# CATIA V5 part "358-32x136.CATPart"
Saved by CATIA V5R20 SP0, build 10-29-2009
Part number: 358-32X136
Definition: NONE
Nomenclature: 358-32X136
Source: Unknown
Description: 358-32X136
Bounding box of the stored display mesh (mm): x -17 to 119, y -22.5 to 22.5, z -22.5 to 22.5
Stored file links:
  C:\Users\Utente\Desktop\IO LAVORO\3D X SITO CF\X SITO\PLASTICA\358\358-32x136.CATPart

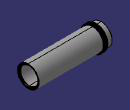
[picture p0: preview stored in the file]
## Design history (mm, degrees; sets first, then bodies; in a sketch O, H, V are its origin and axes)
Body1 "358-32X136" (main body)
  Solid1: solid without history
